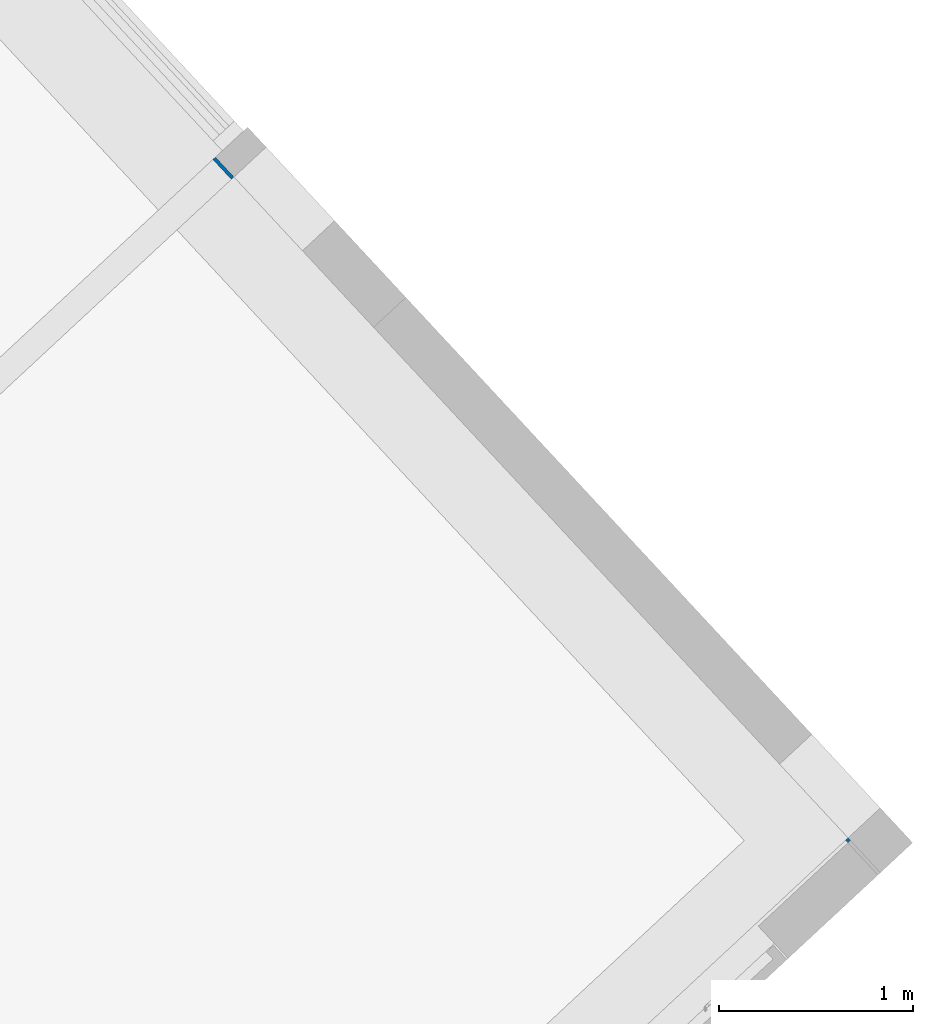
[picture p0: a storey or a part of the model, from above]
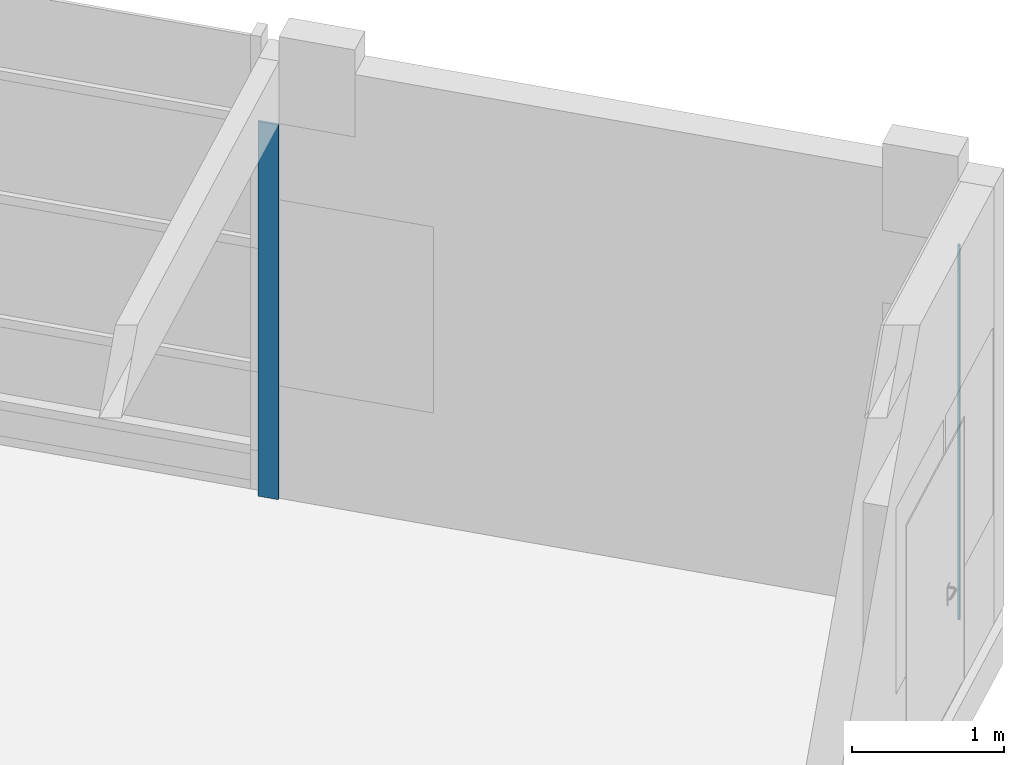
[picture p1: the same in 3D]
Properties of the parts of a building model (IFC2X3)

# File
Description: ViewDefinition [CoordinationView]
File name: ZV002-350-101.2.IFC (Edited by Naviate Simple BIM 2022 version 6)
Time: 2026-03-21T08:07:27+01:00
Written by: ODA SDAI 24.12
Made in: Autodesk Revit 25.4.30.30 (ENU) - IFC 25.4.0.27

# IfcProject, Prosjektnummer
LongName: Prosjektnavn; Phase: Prosjektstatus

# IfcSite, Default
RefLatitude: 59, 54, 57, 599999; RefLongitude: 10, 44, 59, 999999; RefElevation: 0 mm
Other - Project Name: Prosjektnavn; Category: Project Information; Project Status: Prosjektstatus; Project Address: Enter address here; Project Issue Date: Dato; Project Number: Prosjektnummer
Identity Data - Godkjent: AJH; Tiltaket gjelder: Ombygging; Workset: Project Info; Prosjekt: Stavanger lufthavn Sola - Helikopterterminal

# IfcBuilding
Pset_BuildingCommon - NumberOfStoreys: 1
Other - Project Name: Prosjektnavn; Category: Project Information; Project Status: Prosjektstatus; Project Address: Enter address here; Project Issue Date: Dato; Project Number: Prosjektnummer
Identity Data - Godkjent: AJH; Tiltaket gjelder: Ombygging; Workset: Project Info; Prosjekt: Stavanger lufthavn Sola - Helikopterterminal

# IfcBuildingStorey: Level:Nivå 2.5mm, 001-01
LongName: 001-01; Elevation: 4900 mm
Identity Data - Structural: no; Building Story: yes; Name: 001-01; Workset: Shared Levels and Grids
Constraints - Elevation: 4900 mm
Constraints(Type) - Elevation Base: Project Base Point
Other - Type: Nivå 2.5mm; Family and Type: Level: Nivå 2.5mm; Type Id: 305; Category: Levels; Family: Level
Graphics(Type) - Line Pattern: Centre; Color: 0; Symbol at End 1 Default: no; Symbol at End 2 Default: yes; Line Weight: 1; Symbol: Nivåhode : Nivåhode Trekant
Identity Data(Type) - Workset: Level Types; Type Name: Nivå 2.5mm
Dimensions - Computation Height: 1200 mm
Pset_AirSideSystemInformation - Name: 001-01; sets with these values: 2
Other(Type) - Category: Levels; Family Name: Level

# IfcBuildingElementProxy: 933*140 48456:933*140 48456 (3)
In: 001-01
Type - Material: TIMBER/C24
Type - Other - Category: Structural Framing; Family Name: 933*140 48456
Type - Identity Data - Type Name: 933*140 48456; Workset: Family : Structural Framing : 933*140 48456
Type - Materials and Finishes - Material: TIMBER/C24
Type - Structural - Section Shape: 0
Pset_BuildingElementProxyCommon - Reference: 933*140 48456; sets with these values: 2
Constraints - Host: Level : 001-01; Moves With Nearby Elements: no; Level: 001-01
Identity Data - Workset: Workset1
ePset_LocationTool - Splitting: RESULT
Other - Type Id: 785722; Family and Type: 933*140 48456: 933*140 48456; Family: 933*140 48456; Type: 933*140 48456
Structural - Rebar Cover - Top Face: Rebar Cover 1 <25 mm>; Rebar Cover - Other Faces: Rebar Cover 1 <25 mm>; Rebar Cover - Bottom Face: Rebar Cover 1 <25 mm>
ePset_SimplebimBasicQuantities - Volume, net (Simplebim): 0.8498 m3; Thickness (Simplebim): 140 mm; Height (Simplebim): 499 mm; Length (Simplebim): 12140 mm; Area, largest surface, net (Simplebim): 6.07 m2
ePset_Simplebim - Assembly Level: Leaf
Phasing - Phase Created: Final
Group: Model Group:RIB_søyler_Eksisterende:1148207
Name (933*140 48456:933*140 48456:...)
1148341
1148342
1148343

# IfcBuildingElementProxy: Slab Edge:Ringmur 600x300mm, Slab Edge:Ringmur 600x300mm:653989
In: 001-01
Type - Other - Category: Floors: Slab Edges; Family Name: Slab Edge
Type - Construction - Profile: M_Slab Edge-Thickened : 600 x 300mm
Type - Identity Data - Type Name: Ringmur 600x300mm; Workset: Slab Edge Settings
Type - Materials and Finishes - Material: Betong - Plasstøpt
Other - Type: Ringmur 600x300mm; Family and Type: Slab Edge: Ringmur 600x300mm; Family: Slab Edge; Type Id: 106184
Structural - Rebar Cover: Rebar Cover 1 <25 mm>
ePset_SimplebimBasicQuantities - Volume, net (Simplebim): 1.98668 m3; Area, largest surface, net (Simplebim): 8.8297 m2; Height (Simplebim): 300 mm; Thickness (Simplebim): 5448 mm; Length (Simplebim): 9868 mm
Identity Data - Workset: Workset1
Pset_QuantityTakeOff - Reference: Ringmur 600x300mm; sets with these values: 2
ePset_LocationTool - Splitting: RESULT
ePset_Simplebim - Assembly Level: Leaf
Phasing - Phase Created: Final

# IfcColumn: 140*140:140*140 (3)
In: 001-01
Type - PredefinedType: COLUMN; Material: TIMBER/C30
Type - Other - Category: Columns; Family Name: 140*140
Type - Graphics - Coarse Scale Fill Color: 0
Type - Identity Data - Type Name: 140*140; Workset: Family : Columns : 140*140
Type - Materials and Finishes - Material: TIMBER/C30
Pset_QuantityTakeOff - Reference: 140*140; sets with these values: 2
Other - Type Id: 785714; Family: 140*140; Type: 140*140; Family and Type: 140*140: 140*140
Pset_ProductRequirements - Name: Tresøyle
Identity Data - Workset: Workset1
Constraints - Base Offset: 0 mm; Room Bounding: yes; Moves With Grids: yes; Top Offset: 3000 mm; Level: 001-01; Base Level: 001-01; Top Level: 001-01
Phasing - Phase Created: Final
ePset_LocationTool - Splitting: ORIGINAL
ePset_SimplebimBasicQuantities - Height (Simplebim): 3000 mm
ePset_Simplebim - Assembly Level: Leaf
Pset_ColumnCommon - IsExternal: no; Slope: 0 deg; Reference: 140*140
Group: Model Group:RIB_søyler_Eksisterende:1148207
Name (140*140:140*140:...) | Width (Simplebim) (mm) | Area, sides, net (Simplebim) (m2) | Volume, net (Simplebim) (m3) = Volume (m3) | Depth (Simplebim) (mm) | Weight, as steel (Simplebim) (kg)
1148781 | 18 | 0.216 | 0.000972 | 18 | 7.6302
1148782 | 18 | 0.947999 | 0.00756 | 140 | 59.346
1148783 | 140 | 1.68 | 0.0588 | 140 | 461.58

# IfcColumn: 267*140 51386:267*140 51386 (3)
In: 001-01
Type - PredefinedType: COLUMN; Material: TIMBER/C30
Type - Other - Category: Columns; Family Name: 267*140 51386
Type - Graphics - Coarse Scale Fill Color: 0
Type - Identity Data - Type Name: 267*140 51386; Workset: Family : Columns : 267*140 51386
Type - Materials and Finishes - Material: TIMBER/C30
Constraints - Room Bounding: yes; Moves With Grids: yes; Level: 001-01; Base Level: 001-01; Top Level: 001-01
Pset_ProductRequirements - Name: Tresøyle
Other - Type Id: 785728; Family: 267*140 51386; Type: 267*140 51386; Family and Type: 267*140 51386: 267*140 51386
Identity Data - Workset: Workset1
ePset_LocationTool - Splitting: RESULT
Phasing - Phase Created: Final
ePset_Simplebim - Assembly Level: Leaf
Pset_ReinforcementBarPitchOfColumn - Reference: 267*140 51386; sets with these values: 2
ePset_SimplebimBasicQuantities - Area, sides, net (Simplebim): 2.7105 m2; Volume, net (Simplebim): 0.121135 m3; Width (Simplebim): 140 mm; Depth (Simplebim): 267 mm; Height (Simplebim): 3500 mm; Weight, as steel (Simplebim): 950.91 kg
Pset_ColumnCommon - Reference: 267*140 51386; IsExternal: no
Group: Model Group:RIB_søyler_Eksisterende:1148207
Name (267*140 51386:267*140 51386:...)
1148748
1148750
1148752

# IfcCovering: Compound Ceiling:Enkel 57mm, Compound Ceiling:Enkel 57mm:1986693
In: 001-01
Type - PredefinedType: CEILING
Type - Other - Category: Ceilings; Family Name: Compound Ceiling
Type - Construction - Thickness: 57 mm
Type - Graphics - Coarse Scale Fill Color: 0
Type - Identity Data - Type Name: Enkel 57mm; Workset: Ceiling Types
Type - Analytical Properties - Absorptance: 0.1; Roughness: 1
Type - Pset_CoveringCommon - TotalThickness: 57 mm
Material: <Unnamed> 45 mm, Himling rigitone BIG 12 mm
ePset_SimplebimBasicQuantities - Area, largest surface, net (Simplebim): 2.63502 m2; Length (Simplebim): 2013 mm; Volume, net (Simplebim): 0.150196 m3; Height (Simplebim): 57 mm; Width (Simplebim): 1309 mm
Identity Data - Workset: Workset1
Dimensions - Area: 2.63502 m2; Volume: 0.150196 m3; Perimeter: 6644 mm
Constraints - Room Bounding: yes; Height Offset From Level: 2400 mm; Level: 001-01
Phasing - Phase Created: Final
ePset_LocationTool - Splitting: ORIGINAL
ePset_Simplebim - Assembly Level: Leaf
Other - Family: Compound Ceiling; Family and Type: Compound Ceiling: Enkel 57mm; Type: Enkel 57mm; Type Id: 19849
Pset_CoveringCommon - Reference: Enkel 57mm; sets with these values: 2

# IfcCurtainWall: Curtain Wall:Curtain Wall (24dB), Curtain Wall:Curtain Wall (24dB):918602
In: 001-01
Type - Other - Category: Walls; Family Name: Curtain Wall
Type - Construction - Function: Interior; Automatically Embed: yes; Join Condition: Not Defined
Type - Identity Data - Workset: Curtain Wall Types; Lydklasse: R`w 24dB; Type Name: Curtain Wall (24dB)
Type - Horizontal Grid - Adjust for Mullion Size: no
Type - Vertical Grid - Adjust for Mullion Size: no
Structural - Structural Usage: Non-bearing; Structural: no
Constraints - Base is Attached: no; Base Offset: 0 mm; Related to Mass: no; Room Bounding: yes; Top is Attached: no; Top Offset: 0 mm; Unconnected Height: 2690 mm; Base Constraint: 001-01
Pset_QuantityTakeOff - Reference: Curtain Wall (24dB)
Pset_CurtainWallCommon - IsExternal: no; Reference: Curtain Wall (24dB)
Dimensions - Length: 4632 mm; Area: 12.4601 m2
ePset_Simplebim - Assembly Level: Topmost
Phasing - Phase Created: Fase 4A
Other - Family and Type: Curtain Wall: Curtain Wall (24dB); Type: Curtain Wall (24dB); Type Id: 1349679; Family: Curtain Wall
Cross-Section Definition - Cross-Section: Vertical
ePset_SimplebimBasicQuantities - Length: 4632 mm; Width: 176.215 mm; Volume, net (Simplebim): 0.491225 m3; Height: 2690 mm
Identity Data - Mark: GV - H1733; Workset: Workset1
Vertical Grid - Number: 4; Angle: 0 deg; Offset: 0 mm; Justification: Beginning
Horizontal Grid - Angle: 0 deg; Offset: 0 mm; Number: 4; Justification: Beginning

# IfcCurtainWall: Curtain Wall:Curtain Wall 1, Curtain Wall:Curtain Wall 1:301580
In: 001-01
Type - Other(Type) - Category: Walls; Family Name: Curtain Wall
Type - Construction(Type) - Function: Interior; Automatically Embed: yes; Join Condition: Not Defined
Type - Identity Data(Type) - Type Name: Curtain Wall 1; Workset: Curtain Wall Types
Type - Horizontal Grid(Type) - Adjust for Mullion Size: no
Type - Vertical Grid(Type) - Adjust for Mullion Size: no
Structural - Structural Usage: Non-bearing; Structural: no
Dimensions - Length: 14260 mm; Area: 51.8351 m2
Phasing - Phase Created: Fase 3
Pset_CurtainWallCommon - IsExternal: no; Reference: Curtain Wall 1
ePset_Simplebim - Assembly Level: Topmost
Pset_QuantityTakeOff - Reference: Curtain Wall 1
Cross-Section Definition - Cross-Section: Vertical
Identity Data - Workset: Workset1
Other - Family and Type: Curtain Wall: Curtain Wall 1; Type: Curtain Wall 1; Category: Walls; Type Id: 206834; Family: Curtain Wall
Vertical Grid - Number: 4; Angle: 0 deg; Offset: 0 mm; Justification: Beginning
Horizontal Grid - Angle: 0 deg; Offset: 0 mm; Number: 4; Justification: Beginning
Constraints - Base is Attached: no; Base Offset: 0 mm; Related to Mass: no; Room Bounding: yes; Top is Attached: no; Top Constraint: Up to level: 001-02; Top Offset: 385 mm; Unconnected Height: 3635 mm; Base Constraint: 001-01
ePset_SimplebimBasicQuantities - Volume, net (Simplebim): 2.71153 m3; Width: 150 mm; Height: 3635 mm; Length: 14260 mm

# IfcDoor: Enfløyet:Tredør 10x21 grå, Enfløyet:Tredør 10x21 grå:1430291
In: 001-01
Type - OperationType: SINGLE_SWING_RIGHT; ConstructionType: USERDEFINED; ParameterTakesPrecedence: no; Sizeable: no; Material: Rustfritt Stål, mørk grå
Type - IfcDoorPanelProperties - PanelOperation: SWINGING
Type - Other - Category: Doors; Family Name: Enfløyet
Type - Construction - Construction Type: TD Tredør; Dørklinke: Dørklinke - Enkel : Rustfritt; Wall Closure: By host; Terskel: no; Terskeltype: Terskeltype
Type - Identity Data - Model: 10x21M; Type Mark: 10M; Type Name: Tredør 10x21 grå; Workset: Family : Doors : Enfløyet; Fire Rating: Brannkrav; URL: www.cad-q.no; Lydkrav: Lydkrav
Type - Materials and Finishes - Dørbladmateriale: mørk grå; Karmmateriale: mørk grå; Terskelmateriale: mørk grå
Type - Analytical Properties - Define Thermal Properties by: Schematic Type; Analytic Construction: <None>
Type - Pset_ConcreteElementGeneral - ConstructionType: TD Tredør; FireRating: Brannkrav
Type - Pset_DoorCommon - FireRating: Brannkrav
Type - Dimensions - Height: 2090 mm; Width: 990 mm
OverallHeight: 2110 mm; OverallWidth: 1010 mm
Phasing - Phase Created: Fase 3
ePset_SimplebimBasicQuantities - Length, frame (Simplebim): 5170 mm; Height (Simplebim): 2090 mm; Height, opening (Simplebim): 2110 mm; Width, opening (Simplebim): 1010 mm; Area (Simplebim): 2.0691 m2; Width (Simplebim): 990 mm; Area, opening (Simplebim): 2.1311 m2
ePset_LocationTool - Splitting: ORIGINAL
Identity Data - Workset: Workset1; Mark: H1800.6
Other - Family: Enfløyet; Type: Tredør 10x21 grå; Type Id: 293027; Host Id: 1429227; Family and Type: Enfløyet: Tredør 10x21 grå; Head Height: 2090 mm
Dimensions - Innsetting dør: 0 mm; Area: 3.15719 m2; Spalte Side: 10 mm; Spalte Topp: 20 mm; Volume: 0.12902 m3
ePset_Simplebim - Assembly Level: Leaf
Constraints - Sill Height: 0 mm; Level: 001-01
Pset_DoorCommon - Reference: Tredør 10x21 grå; IsExternal: no
Pset_QuantityTakeOff - Reference: Tredør 10x21 grå

# IfcDoor: Tofløyet Ulik:Tredør Tofløyet Sidefelt 10+3x21M, Tofløyet Ulik:Tredør Tofløyet Sidefelt 10+3x21M:1065741
In: 001-01
Type - OperationType: SINGLE_SWING_RIGHT; ConstructionType: USERDEFINED; ParameterTakesPrecedence: no; Sizeable: no; Material: Rustfritt Stål, Aluminium
Type - IfcDoorPanelProperties - PanelOperation: SWINGING
Type - Other - Category: Doors; Family Name: Tofløyet Ulik; M_Height: 21; M_Width: 13; M_Width Sidepanel: 3
Type - Construction - Function: Interior; Construction Type: TD Tredør; Dørklinke: Dørklinke - Enkel : Rustfritt; Wall Closure: By host; Terskel: no; Terskeltype: Terskeltype
Type - Identity Data - Model: (10+3)x21M; Type Mark: D74; Type Name: Tredør Tofløyet Sidefelt 10+3x21M; Workset: Family : Doors : Tofløyet Ulik; DoorBasalOpening: V; Fire Rating: -; URL: www.cad-q.no
Type - Materials and Finishes - Dørbladmateriale: Aluminium; Karmmateriale: Aluminium; Terskelmateriale: Aluminium
Type - Analytical Properties - Define Thermal Properties by: Schematic Type; Analytic Construction: <None>
Type - Pset_ConcreteElementGeneral - ConstructionType: TD Tredør; FireRating: -
Type - Dimensions - Karmbredde: 50 mm; Karmdybde: 100 mm; Rough Height: 2090 mm; Rough Width: 1290 mm; Sidefelt Bredde: 300 mm
Type - Pset_DoorCommon - FireRating: -
OverallHeight: 2110 mm; OverallWidth: 1310 mm
Dimensions - Volume: 0.147788 m3; Veggtykkelse: 227 mm; Area: 3.64765 m2; Innsetting dør: 0 mm; Spalte Side: 10 mm; Spalte Topp: 20 mm; Width: 1310 mm; Height: 2110 mm
Phasing - Phase Created: Fase 3
ePset_SimplebimBasicQuantities - Area (Simplebim): 2.6961 m2; Length, frame (Simplebim): 5470 mm; Height (Simplebim): 2090 mm; Height, opening (Simplebim): 2110 mm; Area, opening (Simplebim): 2.7641 m2; Width (Simplebim): 1290 mm; Width, opening (Simplebim): 1310 mm
Other - Host Id: 232869; Family: Tofløyet Ulik; Type Id: 754215; Head Height: 2110 mm; Type: Tredør Tofløyet Sidefelt 10+3x21M; Family and Type: Tofløyet Ulik: Tredør Tofløyet Sidefelt 10+3x21M
ePset_LocationTool - Splitting: ORIGINAL
Pset_DoorCommon - IsExternal: no; Reference: Tredør Tofløyet Sidefelt 10+3x21M
Pset_QuantityTakeOff - Reference: Tredør Tofløyet Sidefelt 10+3x21M
ePset_Simplebim - Assembly Level: Leaf
Constraints - Sill Height: 0 mm; Level: 001-01
Identity Data - Mark: H1811.2; Workset: Workset1

# IfcFlowTerminal: Sanitærutstyr - Servant Løs:54x33, Sanitærutstyr - Servant Løs:54x33:1542672
In: 001-01
Type - Material: Bad - Hvitevarer
Type - Other - Category: Plumbing Fixtures; CQUnit: pcs; Family Name: Sanitærutstyr - Servant Løs; Monteringshøyde: 900 mm
Type - Constraints - Default Elevation: 0 mm
Type - Identity Data - Type Name: 54x33; Workset: Family : Plumbing Fixtures : Sanitærutstyr - Servant Løs
Constraints - Elevation from Level: 730 mm; Level: 001-01
Other - Type: 54x33; Type Id: 1512759; Family: Sanitærutstyr - Servant Løs; Host Id: 1542596; Family and Type: Sanitærutstyr - Servant Løs: 54x33
Dimensions - Volume: 0.00863352 m3; Area: 0.225128 m2; Dybde: 320 mm; Bredde: 400 mm
Pset_DistributionFlowElementCommon - Reference: 54x33; sets with these values: 2
Phasing - Phase Created: Final
Identity Data - Mark: 176; Workset: Workset1
ePset_LocationTool - Splitting: ORIGINAL
ePset_Simplebim - Assembly Level: Leaf

# IfcFlowTerminal: Sanitærutstyr - WC Vegghengt:Porselen, Sanitærutstyr - WC Vegghengt:Porselen:1541420
In: 001-01
Type - Material: Rustfritt Stål, Porselen
Type - Other - Category: Plumbing Fixtures; CQUnit: pcs; Family Name: Sanitærutstyr - WC Vegghengt
Type - Constraints - Default Elevation: 0 mm
Type - Dimensions - Bredde Veggstativ: 550 mm; Dybde Veggstativ: 150 mm; Høyde Skyllepanel: 950 mm; Monteringshøyde: 410 mm
Type - Identity Data - Type Name: Porselen; Workset: Family : Plumbing Fixtures : Sanitærutstyr - WC Vegghengt
Type - Materials and Finishes - Material Utstyr: Rustfritt Stål; Material WC: Porselen
Type - Plumbing - Vis Veggstativ: yes
Constraints - Elevation from Level: 100 mm; Level: 001-01
Phasing - Phase Created: Fase 3
Dimensions - Samlet Tykkelse Kledning: 36 mm; Area: 0.490272 m2; Volume: 0.0360853 m3
Identity Data - Mark: 173; Workset: Workset1
ePset_LocationTool - Splitting: ORIGINAL
Other - Type: Porselen; Family and Type: Sanitærutstyr - WC Vegghengt: Porselen; Family: Sanitærutstyr - WC Vegghengt; Host Id: 1541278; Type Id: 800139
ePset_Simplebim - Assembly Level: Leaf
Pset_DistributionFlowElementCommon - Reference: Porselen; sets with these values: 2

# IfcGroup: Model Group:RIB_søyler_Eksisterende, Model Group:RIB_søyler_Eksisterende:1148207
Other - Category: Model Groups; Family and Type: Model Group: RIB_søyler_Eksisterende; Family: Model Group; Type Id: 767239; Type: RIB_søyler_Eksisterende
Identity Data(Type) - Type Name: RIB_søyler_Eksisterende; Workset: Workset1
Identity Data - Workset: Workset1
Constraints - Origin Level Offset: 0 mm; Reference Level: 001-01
Other(Type) - Category: Model Groups; Family Name: Model Group

# IfcMember: Rectangular Mullion:50x100mm Aluminium (4)
In: 001-01
Type - PredefinedType: MULLION; Material: Aluminium
Type - Other - Category: Curtain Wall Mullions; Family Name: Rectangular Mullion
Type - Constraints - Angle: 0 deg; Offset: 0 mm
Type - Construction - Corner Mullion: no; Position: Perpendicular to Face; Profile: System Mullion Profile: Rectangular; Thickness: 100 mm
Type - Dimensions - Width on side 1: 25 mm; Width on side 2: 25 mm
Type - Identity Data - Type Name: 50x100mm Aluminium; Workset: Family : Curtain Wall Mullions : Rectangular Mullion
Type - Materials and Finishes - Material: Aluminium
Constraints - Level: 001-01
Pset_MemberCommon - IsExternal: no; Reference: 50x100mm Aluminium
Phasing - Phase Created: Fase 4A
Identity Data - Workset: Workset1
Pset_QuantityTakeOff - Reference: 50x100mm Aluminium
ePset_SimplebimBasicQuantities - Width (Simplebim): 50 mm; Length (Simplebim): 100 mm
ePset_LocationTool - Splitting: ORIGINAL
Other - Family: Rectangular Mullion; Host Id: 918602; Type Id: 618992; Type: 50x100mm Aluminium; Family and Type: Rectangular Mullion: 50x100mm Aluminium
ePset_Simplebim - Assembly Level: Leaf
Name (Rectangular Mullion:50x100mm Aluminium:...) | Span (mm) = Length (mm) = Height (Simplebim) (mm) | Area (m2) | Volume (m3) = Volume, net (Simplebim) (m3) | Area, sides, net (Simplebim) (m2) | Weight, as steel (Simplebim) (kg)
918614 | 590 | 0.0935 | 0.00295 | 0.187 | 23.1575
918629 | 945 | 0.14675 | 0.004725 | 0.2935 | 37.0913
918637 | 577.5 | 0.091625 | 0.0028875 | 0.18325 | 22.6669
1454413 | 577.5 | 0.091625 | 0.0028875 | 0.18325 | 22.6669

# IfcMember: Rectangular Mullion:70x105mm Aluminium (6)
In: 001-01
Type - PredefinedType: MULLION; Material: Aluminium
Type - Other - Category: Curtain Wall Mullions; Family Name: Rectangular Mullion
Type - Constraints - Angle: 0 deg; Offset: 22.5 mm
Type - Construction - Corner Mullion: no; Position: Perpendicular to Face; Profile: System Mullion Profile: Rectangular; Thickness: 105 mm
Type - Dimensions - Width on side 1: 35 mm; Width on side 2: 35 mm
Type - Identity Data - Type Name: 70x105mm Aluminium; Workset: Family : Curtain Wall Mullions : Rectangular Mullion
Type - Materials and Finishes - Material: Aluminium
Constraints - Level: 001-01
Other - Type Id: 1250423; Family: Rectangular Mullion; Type: 70x105mm Aluminium; Host Id: 301580; Family and Type: Rectangular Mullion: 70x105mm Aluminium
Pset_MemberCommon - Reference: 70x105mm Aluminium; IsExternal: no; Span: 2225 mm
Identity Data - Workset: Workset1
Pset_QuantityTakeOff - Reference: 70x105mm Aluminium
Dimensions - Volume: 0.0163537 m3; Length: 2225 mm; Area: 0.396725 m2
ePset_LocationTool - Splitting: ORIGINAL
Phasing - Phase Created: Fase 3
ePset_SimplebimBasicQuantities - Weight, as steel (Simplebim): 128.377 kg; Volume, net (Simplebim): 0.0163537 m3; Length (Simplebim): 2225 mm; Height (Simplebim): 70 mm; Width (Simplebim): 105 mm; Area, sides, net (Simplebim): 0.79345 m2
ePset_Simplebim - Assembly Level: Leaf
Name (Rectangular Mullion:70x105mm Aluminium:...)
486451
486480
486489
486515
486532
486534

# IfcMember: Rectangular Mullion:70x150mm Aluminium (18)
In: 001-01
Type - PredefinedType: MULLION; Material: Aluminium
Type - Other - Category: Curtain Wall Mullions; Family Name: Rectangular Mullion
Type - Constraints - Angle: 0 deg; Offset: 0 mm
Type - Construction - Corner Mullion: no; Position: Perpendicular to Face; Profile: System Mullion Profile: Rectangular; Thickness: 150 mm
Type - Dimensions - Width on side 1: 35 mm; Width on side 2: 35 mm
Type - Identity Data - Type Name: 70x150mm Aluminium; Workset: Family : Curtain Wall Mullions : Rectangular Mullion
Type - Materials and Finishes - Material: Aluminium
Constraints - Level: 001-01
Identity Data - Workset: Workset1
Pset_QuantityTakeOff - Reference: 70x150mm Aluminium
ePset_LocationTool - Splitting: ORIGINAL
Pset_MemberCommon - Reference: 70x150mm Aluminium; IsExternal: no
Phasing - Phase Created: Fase 3
Other - Family: Rectangular Mullion; Host Id: 301580; Type: 70x150mm Aluminium; Type Id: 1249671; Family and Type: Rectangular Mullion: 70x150mm Aluminium
ePset_Simplebim - Assembly Level: Leaf
Name (Rectangular Mullion:70x150mm Aluminium:...) | Height (Simplebim) (mm) | Length (Simplebim) (mm) | Area, sides, net (Simplebim) (m2) | Weight, as steel (Simplebim) (kg) | Width (Simplebim) (mm) | Volume, net (Simplebim) (m3) = Volume (m3) | Length (mm) = Span (mm) | Area (m2)
486454 | 710 | 150 | 0.3334 | 58.5217 | 70 | 0.007455 | 710 | 0.1667
486456 | 990 | 150 | 0.4566 | 81.6008 | 70 | 0.010395 | 990 | 0.2283
486458 | 990 | 150 | 0.4566 | 81.6008 | 70 | 0.010395 | 990 | 0.2283
486463 | 710 | 150 | 0.3334 | 58.5217 | 70 | 0.007455 | 710 | 0.1667
486465 | 990 | 150 | 0.4566 | 81.6008 | 70 | 0.010395 | 990 | 0.2283
486467 | 990 | 150 | 0.4566 | 81.6008 | 70 | 0.010395 | 990 | 0.2283
486504 | 70 | 2260 | 1.0154 | 186.28 | 150 | 0.02373 | 2260 | 0.5077
486510 | 315 | 150 | 0.1596 | 25.9639 | 70 | 0.0033075 | 315 | 0.0798
486512 | 70 | 2260 | 1.0154 | 186.28 | 150 | 0.02373 | 2260 | 0.5077
486521 | 990 | 150 | 0.4566 | 81.6008 | 70 | 0.010395 | 990 | 0.2283
486523 | 630 | 150 | 0.2982 | 51.9278 | 70 | 0.006615 | 630 | 0.1491
486527 | 990 | 150 | 0.4566 | 81.6008 | 70 | 0.010395 | 990 | 0.2283
532713 | 665 | 150 | 0.3136 | 54.8126 | 70 | 0.0069825 | 665 | 0.1568
532716 | 630 | 150 | 0.2982 | 51.9278 | 70 | 0.006615 | 630 | 0.1491
532723 | 315 | 150 | 0.1596 | 25.9639 | 70 | 0.0033075 | 315 | 0.0798
532915 | 70 | 2225 | 1 | 183.396 | 150 | 0.0233625 | 2225 | 0.5
532919 | 70 | 2225 | 1 | 183.396 | 150 | 0.0233625 | 2225 | 0.5
1251068 | 710 | 150 | 0.3334 | 58.5217 | 70 | 0.007455 | 710 | 0.1667

# IfcPlate: System Panel:Glassfelt 25mm (8)
In: 001-01
Type - PredefinedType: CURTAIN_PANEL; Material: Glass
Type - Other - Category: Curtain Panels; Family Name: System Panel
Type - Constraints - Offset: 25 mm
Type - Dimensions - Thickness: 25 mm
Type - Identity Data - Type Name: Glassfelt 25mm; Workset: Family : Curtain Panels : System Panel
Type - Materials and Finishes - Material: Glass
Type - Analytical Properties - Define Thermal Properties by: Schematic Type; Analytic Construction: <None>
Other - Host Id: 301580; Type Id: 12611; Family and Type: System Panel: Glassfelt 25mm; Type: Glassfelt 25mm; Family: System Panel
Pset_QuantityTakeOff - Reference: Glassfelt 25mm
Constraints - Level: 001-01
Dimensions - Width: 2225 mm
Identity Data - Workset: Workset1
Phasing - Phase Created: Fase 3
Pset_PlateCommon - IsExternal: no; Reference: Glassfelt 25mm
ePset_Simplebim - Assembly Level: Leaf
ePset_LocationTool - Splitting: ORIGINAL
Name (System Panel:Glassfelt 25mm:...) | Area (m2) | Volume (m3) = Volume, net (Simplebim) (m3) | Height (mm) | Area, largest surface, net (Simplebim) (m2) | Weight, as steel (Simplebim) (kg)
532688 | 1.246 | 0.03115 | 560 | 1.246 | 244.527
532691 | 1.246 | 0.03115 | 560 | 1.246 | 244.527
485947 | 2.047 | 0.051175 | 920 | 2.047 | 401.724
486063 | 2.047 | 0.051175 | 920 | 2.047 | 401.724
485886 | 2.047 | 0.051175 | 920 | 2.047 | 401.724
486064 | 2.047 | 0.051175 | 920 | 2.047 | 401.724
485801 | 1.34612 | 0.0336531 | 605 | 1.34613 | 264.177
486065 | 1.34612 | 0.0336531 | 605 | 1.34613 | 264.177

# IfcPlate: System Panel:Tettfelt 150mm (2)
In: 001-01
Type - PredefinedType: CURTAIN_PANEL; Material: Aluminium
Type - Other - Category: Curtain Panels; Family Name: System Panel
Type - Constraints - Offset: 0 mm
Type - Dimensions - Thickness: 150 mm
Type - Identity Data - Type Name: Tettfelt 150mm; Workset: Family : Curtain Panels : System Panel
Type - Materials and Finishes - Material: Aluminium
Type - Analytical Properties - Define Thermal Properties by: Schematic Type; Analytic Construction: <None>
Constraints - Level: 001-01
Pset_QuantityTakeOff - Reference: Tettfelt 150mm
Identity Data - Workset: Workset1
Other - Family and Type: System Panel: Tettfelt 150mm; Type Id: 687138; Host Id: 301580; Type: Tettfelt 150mm; Family: System Panel
ePset_LocationTool - Splitting: ORIGINAL
Phasing - Phase Created: Fase 3
Pset_PlateCommon - IsExternal: no; Reference: Tettfelt 150mm
ePset_Simplebim - Assembly Level: Leaf
Name (System Panel:Tettfelt 150mm:...) | Area (m2) | Width (mm) | Height (mm) | Volume (m3) = Volume, net (Simplebim) (m3) | Area, largest surface, net (Simplebim) (m2) | Weight, as steel (Simplebim) (kg)
301581 | 0.9492 | 4520 | 210 | 0.14238 | 0.9492 | 1117.68
305155 | 0.5089 | 140 | 3635 | 0.076335 | 0.54525 | 599.23

# IfcSlab: Floor:Betong Plasstøpt 150mm, Floor:Betong Plasstøpt 150mm:653308
In: 001-01
Type - PredefinedType: FLOOR; Material: Betong - Plasstøpt 150 mm
Type - Other - Category: Floors; Family Name: Floor
Type - Construction - Function: Interior; Default Thickness: 150 mm
Type - Graphics - Coarse Scale Fill Color: 0
Type - Identity Data - Type Name: Betong Plasstøpt 150mm; Workset: Floor Types
Type - Materials and Finishes - Structural Material: Betong - Plasstøpt
Type - Analytical Properties - Absorptance: 0.1; Roughness: 1
Constraints - Related to Mass: no; Room Bounding: yes; Level: 001-01
ePset_SimplebimBasicQuantities - Area, largest surface, net (Simplebim): 120.609 m2; Perimeter (Simplebim): 44180.4 mm; Area, sides, net (Simplebim): 6.62706 m2; Area, top, net (Simplebim): 120.609 m2; Thickness (Simplebim): 150 mm; Volume, net (Simplebim): 18.0913 m3
Pset_ReinforcementBarPitchOfSlab - Reference: Betong Plasstøpt 150mm; sets with these values: 2
Pset_SlabCommon - Reference: Betong Plasstøpt 150mm; IsExternal: no; LoadBearing: no
Identity Data - Has Association: no; Workset: Workset1
ePset_LocationTool - Splitting: RESULT
Other - Type Id: 106384; Family and Type: Floor: Betong Plasstøpt 150mm; Type: Betong Plasstøpt 150mm; Family: Floor
Phasing - Phase Created: Fase 5
Structural - Structural: no
ePset_Simplebim - Assembly Level: Leaf

# IfcWall: Basic Wall:YV 1_ Tre 148 Isolert Stående Kledning (4)
In: 001-01
Type - PredefinedType: STANDARD; Material: Vegg - Dobbelfals Stående Kledning - HVIT 19 mm, Vegg - Utlekting 36 mm, Vegg - Asfaltplate 12 mm, Vegg - Konstruksjon Fylt grå 148 mm, Vegg - Veggplater 12 mm
Type - Other - Category: Walls; Family Name: Basic Wall
Type - Construction - Function: Interior; Width: 227 mm; Wrapping at Inserts: Do not wrap
Type - Graphics - Coarse Scale Fill Color: 0
Type - Identity Data - Type Name: YV 1_ Tre 148 Isolert Stående Kledning; Workset: Wall Types
Type - Materials and Finishes - Structural Material: Vegg - Konstruksjon Fylt grå
Type - Analytical Properties - Absorptance: 0.1; Roughness: 1
Structural - Structural Usage: Non-bearing; Structural: no
Constraints - Related to Mass: no
Other - Family: Basic Wall; Type Id: 234434; Type: YV 1_ Tre 148 Isolert Stående Kledning; Family and Type: Basic Wall: YV 1_ Tre 148 Isolert Stående Kledning
Pset_QuantityTakeOff - Reference: YV 1_ Tre 148 Isolert Stående Kledning; sets with these values: 2
Identity Data - Workset: Workset1
Pset_WallCommon - IsExternal: no; ExtendToStructure: no; LoadBearing: no; Reference: YV 1_ Tre 148 Isolert Stående Kledning
ePset_Simplebim - Assembly Level: Leaf
Name (Basic Wall:YV 1_ Tre 148 Isolert Stående Kledning:...) | Volume, net (Simplebim) (m3) | Area, largest surface, net (Simplebim) (m2) = Area, side, net, average (Simplebim) (m2) = Area, side, net, larger (Simplebim) (m2) = Area, side, net, smaller (Simplebim) (m2) | Area, side, gross, average (Simplebim) (m2) = Area, side, gross, larger (Simplebim) (m2) = Area, side, gross, smaller (Simplebim) (m2) | Area, side, gross, AABB (Simplebim) (m2) | Thickness (Simplebim) (mm) | Length (Simplebim) (mm) | Height (Simplebim) (mm) | Location Line | Splitting
705822 | 0.12835 | 0.56542 | 0.56542 | 1.5794 | 227 | 1060 | 1490 | Wall Centerline | ORIGINAL | Dimensions - Volume: 0.12835 m3; Area: 0.56542 m2; Constraints - Base Extension Distance: 0 mm; Top Extension Distance: 0 mm
1065691 | 0.240965 | 1.06152 | 1.06152 | 1.5794 | 227 | 1060 | 1490 | Wall Centerline | ORIGINAL | Dimensions - Volume: 0.240965 m3; Area: 1.06152 m2; Constraints - Base Extension Distance: 0 mm; Top Extension Distance: 0 mm
232663 | 3.35227 | 14.7677 | 80.7011 | 17.6575 | 228 | 5045 | 3500 | Core Face: Interior | RESULT | Cross-Section Definition - Cross-Section: Vertical; Phasing - Phase Created: Eksisterende; Constraints - Base is Attached: no; Room Bounding: yes; Top is Attached: no; Top Constraint: Up to level: Topp gesims; Base Constraint: 001-01
232869 | 2.64443 | 11.6495 | 17.5724 | 16.0405 | 228 | 4583 | 3500 | Core Face: Interior | RESULT | Cross-Section Definition - Cross-Section: Vertical; Phasing - Phase Created: Eksisterende; Constraints - Base is Attached: no; Room Bounding: yes; Top is Attached: no; Top Constraint: Up to level: Topp gesims; Base Constraint: 001-01

# IfcWallStandardCase: Basic Wall:Innervegg - 100mm Stender 2+0 Gips (2)
In: 001-01
Type - PredefinedType: STANDARD; Material: Gips 13 mm, Gips 13 mm, Isolasjon 100 mm
Type - Other - Category: Walls; Family Name: Basic Wall
Type - Construction - Function: Interior; Width: 126 mm; Wrapping at Inserts: Do not wrap
Type - Graphics - Coarse Scale Fill Color: 0
Type - Identity Data - Type Name: Innervegg - 100mm Stender 2+0 Gips; Workset: Wall Types
Type - Materials and Finishes - Structural Material: Isolasjon
Type - Analytical Properties - Absorptance: 0.1; Roughness: 1
Cross-Section Definition - Cross-Section: Vertical
Constraints - Base Extension Distance: 0 mm; Base is Attached: no; Base Offset: 0 mm; Related to Mass: no; Room Bounding: yes; Top Extension Distance: 0 mm; Top is Attached: no; Top Constraint: Up to level: 001-02; Top Offset: -250 mm; Unconnected Height: 3000 mm; Base Constraint: 001-01
Structural - Structural Usage: Non-bearing; Structural: no
ePset_LocationTool - Splitting: ORIGINAL
Phasing - Phase Created: Fase 3
ePset_SimplebimBasicQuantities - Thickness (Simplebim): 126 mm; Height (Simplebim): 3000 mm
Pset_QuantityTakeOff - Reference: Innervegg - 100mm Stender 2+0 Gips; sets with these values: 2
Identity Data - Workset: Workset1
Pset_WallCommon - IsExternal: no; ExtendToStructure: no; LoadBearing: no; Reference: Innervegg - 100mm Stender 2+0 Gips
Other - Family: Basic Wall; Family and Type: Basic Wall: Innervegg - 100mm Stender 2+0 Gips; Type: Innervegg - 100mm Stender 2+0 Gips; Type Id: 1429036
ePset_Simplebim - Assembly Level: Leaf
Name (Basic Wall:Innervegg - 100mm Stender 2+0 Gips:...) | Location Line | Area (m2) = Area, side, net, average (Simplebim) (m2) = Area, largest surface, net (Simplebim) (m2) = Area, side, gross, average (Simplebim) (m2) = Area, side, gross, larger (Simplebim) (m2) = Area, side, gross, smaller (Simplebim) (m2) = Area, side, net, larger (Simplebim) (m2) = Area, side, net, smaller (Simplebim) (m2) = Area, side, gross, AABB (Simplebim) (m2) | Length (mm) | Volume (m3) = Volume, net (Simplebim) (m3) | Length (Simplebim) (mm)
1429202 | Finish Face: Exterior | 4.305 | 1448 | 0.534732 | 1435
1435927 | Core Face: Interior | 6.8445 | 2344.5 | 0.862407 | 2281.5

# IfcWallStandardCase: Basic Wall:Innervegg - 100mm Stender 2+0 Gips (wrap), Basic Wall:Innervegg - 100mm Stender 2+0 Gips (wrap):1542596
In: 001-01
Type - PredefinedType: STANDARD; Material: Gips 13 mm, Gips 13 mm, Isolasjon 100 mm
Type - Other - Category: Walls; Family Name: Basic Wall
Type - Construction - Function: Interior; Width: 126 mm; Wrapping at Ends: Exterior; Wrapping at Inserts: Do not wrap
Type - Graphics - Coarse Scale Fill Color: 0
Type - Identity Data - Type Name: Innervegg - 100mm Stender 2+0 Gips (wrap); Workset: Wall Types
Type - Materials and Finishes - Structural Material: Isolasjon
Type - Analytical Properties - Absorptance: 0.1; Roughness: 1
Cross-Section Definition - Cross-Section: Vertical
Pset_QuantityTakeOff - Reference: Innervegg - 100mm Stender 2+0 Gips (wrap); sets with these values: 2
Phasing - Phase Created: Final
ePset_SimplebimBasicQuantities - Volume, net (Simplebim): 0.151729 m3; Area, largest surface, net (Simplebim): 1.2042 m2; Area, side, net, average (Simplebim): 1.2042 m2; Area, side, gross, average (Simplebim): 1.2042 m2; Area, side, gross, larger (Simplebim): 1.2042 m2; Area, side, net, larger (Simplebim): 1.2042 m2; Area, side, gross, smaller (Simplebim): 1.2042 m2; Area, side, net, smaller (Simplebim): 1.2042 m2; Area, side, gross, AABB (Simplebim): 1.2042 m2; Thickness (Simplebim): 126 mm; Length (Simplebim): 1003.5 mm; Height (Simplebim): 1200 mm
Structural - Structural Usage: Non-bearing; Structural: no
Dimensions - Length: 1135 mm; Volume: 0.151729 m3; Area: 1.2042 m2
Pset_WallCommon - IsExternal: no; ExtendToStructure: no; LoadBearing: no; Reference: Innervegg - 100mm Stender 2+0 Gips (wrap)
Identity Data - Workset: Workset1
Other - Family: Basic Wall; Type Id: 1543019; Type: Innervegg - 100mm Stender 2+0 Gips (wrap); Family and Type: Basic Wall: Innervegg - 100mm Stender 2+0 Gips (wrap)
Constraints - Base Extension Distance: 0 mm; Base is Attached: no; Base Offset: 0 mm; Related to Mass: no; Room Bounding: yes; Top Extension Distance: 0 mm; Top is Attached: no; Top Offset: 0 mm; Location Line: Finish Face: Interior; Unconnected Height: 1200 mm; Base Constraint: 001-01
ePset_Simplebim - Assembly Level: Leaf
ePset_LocationTool - Splitting: ORIGINAL

# IfcWallStandardCase: Basic Wall:Innervegg - 100mm Stender 2+2 Gips (3)
In: 001-01
Type - PredefinedType: STANDARD; Material: Gips 13 mm, Gips 13 mm, Isolasjon 100 mm, Gips 13 mm, Gips 13 mm
Type - Other - Category: Walls; Family Name: Basic Wall
Type - Construction - Function: Interior; Width: 152 mm; Wrapping at Inserts: Do not wrap
Type - Graphics - Coarse Scale Fill Color: 0
Type - Identity Data - Type Name: Innervegg - 100mm Stender 2+2 Gips; Workset: Wall Types
Type - Materials and Finishes - Structural Material: Isolasjon
Type - Analytical Properties - Absorptance: 0.1; Roughness: 1
Cross-Section Definition - Cross-Section: Vertical
Structural - Structural Usage: Non-bearing; Structural: no
ePset_LocationTool - Splitting: ORIGINAL
Phasing - Phase Created: Fase 3
Other - Family: Basic Wall; Family and Type: Basic Wall: Innervegg - 100mm Stender 2+2 Gips; Type: Innervegg - 100mm Stender 2+2 Gips; Type Id: 1194448
Pset_QuantityTakeOff - Reference: Innervegg - 100mm Stender 2+2 Gips; sets with these values: 2
Pset_WallCommon - IsExternal: no; ExtendToStructure: no; LoadBearing: no; Reference: Innervegg - 100mm Stender 2+2 Gips
Identity Data - Workset: Workset1
ePset_SimplebimBasicQuantities - Thickness (Simplebim): 152 mm; Height (Simplebim): 3000 mm
Constraints - Base Extension Distance: 0 mm; Base is Attached: no; Base Offset: 0 mm; Related to Mass: no; Room Bounding: yes; Top Extension Distance: 0 mm; Top is Attached: no; Top Constraint: Up to level: 001-02; Top Offset: -250 mm; Unconnected Height: 3000 mm; Base Constraint: 001-01; Location Line: Core Face: Interior
ePset_Simplebim - Assembly Level: Leaf
Name (Basic Wall:Innervegg - 100mm Stender 2+2 Gips:...) | Length (mm) | Area (m2) = Area, side, net, larger (Simplebim) (m2) = Area, side, net, smaller (Simplebim) (m2) = Area, largest surface, net (Simplebim) (m2) = Area, side, net, average (Simplebim) (m2) | Volume (m3) = Volume, net (Simplebim) (m3) | Length (Simplebim) (mm) | Area, side, gross, AABB (Simplebim) (m2) = Area, side, gross, larger (Simplebim) (m2) = Area, side, gross, smaller (Simplebim) (m2) = Area, side, gross, average (Simplebim) (m2)
254886 | 4811 | 14.064 | 2.13757 | 4688 | 14.064
1428705 | 1365 | 4.323 | 0.657096 | 1441 | 4.323
1429227 | 2413 | 4.6909 | 0.713017 | 2274 | 6.822

# IfcWallStandardCase: Basic Wall:Innervegg - 250mm Stender 1+0 Gips, Basic Wall:Innervegg - 250mm Stender 1+0 Gips:1541278
In: 001-01
Type - PredefinedType: STANDARD; Material: Gips 13 mm, Isolasjon 250 mm
Type - Other - Category: Walls; Family Name: Basic Wall
Type - Construction - Function: Interior; Width: 263 mm; Wrapping at Inserts: Do not wrap
Type - Graphics - Coarse Scale Fill Color: 0
Type - Identity Data - Type Name: Innervegg - 250mm Stender 1+0 Gips; Workset: Wall Types
Type - Materials and Finishes - Structural Material: Isolasjon
Type - Analytical Properties - Absorptance: 0.1; Roughness: 1
Cross-Section Definition - Cross-Section: Vertical
Constraints - Base Extension Distance: 0 mm; Base is Attached: no; Base Offset: 0 mm; Related to Mass: no; Room Bounding: yes; Top Extension Distance: 0 mm; Top is Attached: no; Top Offset: 0 mm; Location Line: Finish Face: Interior; Unconnected Height: 3000 mm; Base Constraint: 001-01
Structural - Structural Usage: Non-bearing; Structural: no
Other - Type: Innervegg - 250mm Stender 1+0 Gips; Family: Basic Wall; Family and Type: Basic Wall: Innervegg - 250mm Stender 1+0 Gips; Type Id: 1544100
Pset_WallCommon - Reference: Innervegg - 250mm Stender 1+0 Gips; IsExternal: no; ExtendToStructure: no; LoadBearing: no
Phasing - Phase Created: Fase 3
ePset_LocationTool - Splitting: ORIGINAL
Pset_ReinforcementBarPitchOfWall - Reference: Innervegg - 250mm Stender 1+0 Gips; sets with these values: 2
Identity Data - Workset: Workset1
ePset_SimplebimBasicQuantities - Area, side, gross, AABB (Simplebim): 3.927 m2; Area, side, gross, average (Simplebim): 3.927 m2; Area, largest surface, net (Simplebim): 3.927 m2; Area, side, net, average (Simplebim): 3.927 m2; Area, side, net, smaller (Simplebim): 3.927 m2; Area, side, net, larger (Simplebim): 3.927 m2; Area, side, gross, smaller (Simplebim): 3.927 m2; Area, side, gross, larger (Simplebim): 3.927 m2; Thickness (Simplebim): 263 mm; Length (Simplebim): 1309 mm; Height (Simplebim): 3000 mm; Volume, net (Simplebim): 1.0328 m3
Dimensions - Area: 3.927 m2; Length: 1322 mm; Volume: 1.0328 m3
ePset_Simplebim - Assembly Level: Leaf

# IfcWallStandardCase: Basic Wall:YV 1_ Tre 148 Isolert Stående Kledning (4)
In: 001-01
Type - PredefinedType: STANDARD; Material: Vegg - Dobbelfals Stående Kledning - HVIT 19 mm, Vegg - Utlekting 36 mm, Vegg - Asfaltplate 12 mm, Vegg - Konstruksjon Fylt grå 148 mm, Vegg - Veggplater 12 mm
Type - Other - Category: Walls; Family Name: Basic Wall
Type - Construction - Function: Interior; Width: 227 mm; Wrapping at Inserts: Do not wrap
Type - Graphics - Coarse Scale Fill Color: 0
Type - Identity Data - Type Name: YV 1_ Tre 148 Isolert Stående Kledning; Workset: Wall Types
Type - Materials and Finishes - Structural Material: Vegg - Konstruksjon Fylt grå
Type - Analytical Properties - Absorptance: 0.1; Roughness: 1
ePset_SimplebimBasicQuantities - Thickness (Simplebim): 227 mm
Structural - Structural Usage: Non-bearing; Structural: no
Constraints - Location Line: Wall Centerline; Base Extension Distance: 0 mm; Related to Mass: no; Top Extension Distance: 0 mm
Other - Family: Basic Wall; Type Id: 234434; Type: YV 1_ Tre 148 Isolert Stående Kledning; Family and Type: Basic Wall: YV 1_ Tre 148 Isolert Stående Kledning
Pset_QuantityTakeOff - Reference: YV 1_ Tre 148 Isolert Stående Kledning; sets with these values: 2
Identity Data - Workset: Workset1
Pset_WallCommon - IsExternal: no; ExtendToStructure: no; LoadBearing: no; Reference: YV 1_ Tre 148 Isolert Stående Kledning
ePset_LocationTool - Splitting: ORIGINAL
ePset_Simplebim - Assembly Level: Leaf
Name (Basic Wall:YV 1_ Tre 148 Isolert Stående Kledning:...) | Area, side, gross, AABB (Simplebim) (m2) = Area, side, net, smaller (Simplebim) (m2) = Area, side, gross, larger (Simplebim) (m2) = Area, side, net, larger (Simplebim) (m2) = Area, side, gross, smaller (Simplebim) (m2) = Area, largest surface, net (Simplebim) (m2) = Area, side, net, average (Simplebim) (m2) = Area, side, gross, average (Simplebim) (m2) = Area (m2) | Volume, net (Simplebim) (m3) = Volume (m3) | Length (Simplebim) (mm) | Height (Simplebim) (mm)
705920 | 0.7904 | 0.179421 | 520 | 1520
706185 | 1.5794 | 0.358524 | 1060 | 1490
707852 | 0.36192 | 0.0821558 | 520 | 696
1029698 | 0.36192 | 0.0821558 | 520 | 696
